VERSION 5.8 ;
BUSBITCHARS "[]" ;
DIVIDERCHAR "/" ;
UNITS
    DATABASE MICRONS 1000 ;
END UNITS

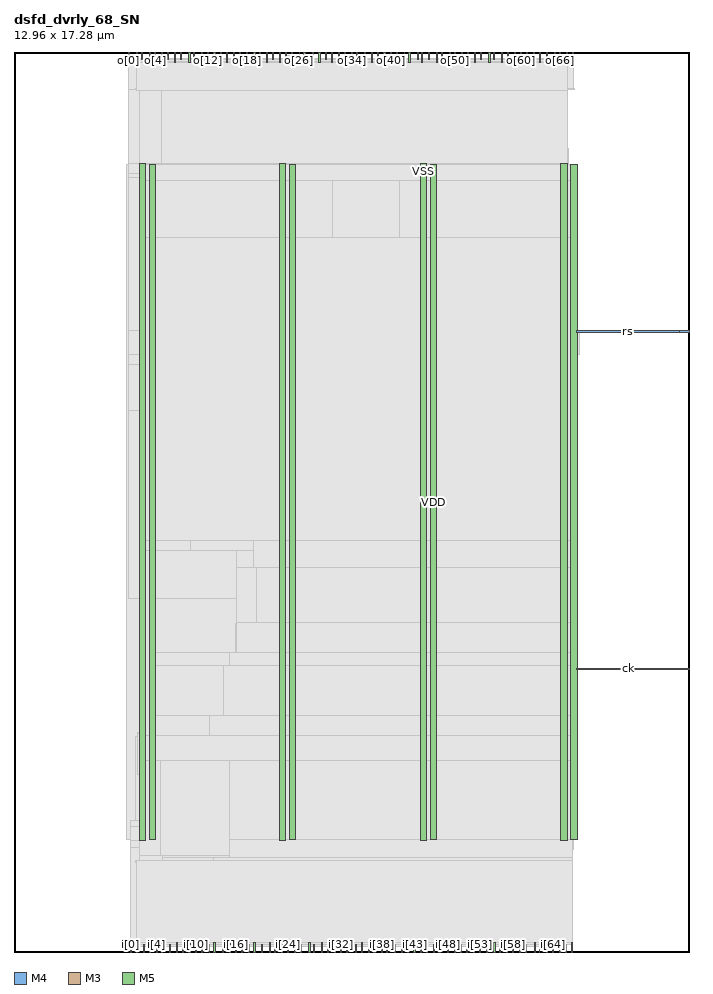
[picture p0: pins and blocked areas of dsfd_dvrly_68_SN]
MACRO dsfd_dvrly_68_SN
  FOREIGN dsfd_dvrly_68_SN 0 0 ;
  CLASS BLOCK ;
  SIZE 12.96 BY 17.28 ;
  PIN ck
    DIRECTION INPUT ;
    USE SIGNAL ;
    PORT
      LAYER M4 ;
        RECT  12.768 5.424 12.96 5.448 ;
    END
    PORT
      LAYER M4 ;
        RECT  10.804 5.424 12.78 5.448 ;
    END
  END ck
  PIN ck_o
    DIRECTION OUTPUT ;
    USE SIGNAL ;
    PORT
      LAYER M3 ;
        RECT  10.728 17.136 10.746 17.28 ;
    END
  END ck_o
  PIN i[0]
    DIRECTION INPUT ;
    USE SIGNAL ;
    PORT
      LAYER M3 ;
        RECT  2.232 0 2.25 0.144 ;
    END
  END i[0]
  PIN i[10]
    DIRECTION INPUT ;
    USE SIGNAL ;
    PORT
      LAYER M3 ;
        RECT  3.492 0 3.51 0.144 ;
    END
  END i[10]
  PIN i[11]
    DIRECTION INPUT ;
    USE SIGNAL ;
    PORT
      LAYER M5 ;
        RECT  3.6 0 3.624 0.192 ;
    END
  END i[11]
  PIN i[12]
    DIRECTION INPUT ;
    USE SIGNAL ;
    PORT
      LAYER M3 ;
        RECT  3.744 0 3.762 0.144 ;
    END
  END i[12]
  PIN i[13]
    DIRECTION INPUT ;
    USE SIGNAL ;
    PORT
      LAYER M5 ;
        RECT  3.84 0 3.864 0.192 ;
    END
  END i[13]
  PIN i[14]
    DIRECTION INPUT ;
    USE SIGNAL ;
    PORT
      LAYER M3 ;
        RECT  3.996 0 4.014 0.144 ;
    END
  END i[14]
  PIN i[15]
    DIRECTION INPUT ;
    USE SIGNAL ;
    PORT
      LAYER M5 ;
        RECT  4.128 0 4.152 0.192 ;
    END
  END i[15]
  PIN i[16]
    DIRECTION INPUT ;
    USE SIGNAL ;
    PORT
      LAYER M3 ;
        RECT  4.248 0 4.266 0.144 ;
    END
  END i[16]
  PIN i[17]
    DIRECTION INPUT ;
    USE SIGNAL ;
    PORT
      LAYER M5 ;
        RECT  4.368 0 4.392 0.192 ;
    END
  END i[17]
  PIN i[18]
    DIRECTION INPUT ;
    USE SIGNAL ;
    PORT
      LAYER M3 ;
        RECT  4.5 0 4.518 0.144 ;
    END
  END i[18]
  PIN i[19]
    DIRECTION INPUT ;
    USE SIGNAL ;
    PORT
      LAYER M5 ;
        RECT  4.608 0 4.632 0.192 ;
    END
  END i[19]
  PIN i[1]
    DIRECTION INPUT ;
    USE SIGNAL ;
    PORT
      LAYER M5 ;
        RECT  2.352 0 2.376 0.192 ;
    END
  END i[1]
  PIN i[20]
    DIRECTION INPUT ;
    USE SIGNAL ;
    PORT
      LAYER M3 ;
        RECT  4.752 0 4.77 0.144 ;
    END
  END i[20]
  PIN i[21]
    DIRECTION INPUT ;
    USE SIGNAL ;
    PORT
      LAYER M5 ;
        RECT  4.896 0 4.92 0.192 ;
    END
  END i[21]
  PIN i[22]
    DIRECTION INPUT ;
    USE SIGNAL ;
    PORT
      LAYER M3 ;
        RECT  5.004 0 5.022 0.144 ;
    END
  END i[22]
  PIN i[23]
    DIRECTION INPUT ;
    USE SIGNAL ;
    PORT
      LAYER M5 ;
        RECT  5.136 0 5.16 0.192 ;
    END
  END i[23]
  PIN i[24]
    DIRECTION INPUT ;
    USE SIGNAL ;
    PORT
      LAYER M3 ;
        RECT  5.256 0 5.274 0.144 ;
    END
  END i[24]
  PIN i[25]
    DIRECTION INPUT ;
    USE SIGNAL ;
    PORT
      LAYER M5 ;
        RECT  5.376 0 5.4 0.192 ;
    END
  END i[25]
  PIN i[26]
    DIRECTION INPUT ;
    USE SIGNAL ;
    PORT
      LAYER M3 ;
        RECT  5.508 0 5.526 0.144 ;
    END
  END i[26]
  PIN i[27]
    DIRECTION INPUT ;
    USE SIGNAL ;
    PORT
      LAYER M5 ;
        RECT  5.664 0 5.688 0.192 ;
    END
  END i[27]
  PIN i[28]
    DIRECTION INPUT ;
    USE SIGNAL ;
    PORT
      LAYER M3 ;
        RECT  5.76 0 5.778 0.144 ;
    END
  END i[28]
  PIN i[29]
    DIRECTION INPUT ;
    USE SIGNAL ;
    PORT
      LAYER M5 ;
        RECT  5.904 0 5.928 0.192 ;
    END
  END i[29]
  PIN i[2]
    DIRECTION INPUT ;
    USE SIGNAL ;
    PORT
      LAYER M3 ;
        RECT  2.484 0 2.502 0.144 ;
    END
  END i[2]
  PIN i[30]
    DIRECTION INPUT ;
    USE SIGNAL ;
    PORT
      LAYER M3 ;
        RECT  6.012 0 6.03 0.144 ;
    END
  END i[30]
  PIN i[31]
    DIRECTION INPUT ;
    USE SIGNAL ;
    PORT
      LAYER M5 ;
        RECT  6.144 0 6.168 0.192 ;
    END
  END i[31]
  PIN i[32]
    DIRECTION INPUT ;
    USE SIGNAL ;
    PORT
      LAYER M3 ;
        RECT  6.264 0 6.282 0.144 ;
    END
  END i[32]
  PIN i[33]
    DIRECTION INPUT ;
    USE SIGNAL ;
    PORT
      LAYER M5 ;
        RECT  6.384 0 6.408 0.192 ;
    END
  END i[33]
  PIN i[34]
    DIRECTION INPUT ;
    USE SIGNAL ;
    PORT
      LAYER M3 ;
        RECT  6.552 0 6.57 0.144 ;
    END
  END i[34]
  PIN i[35]
    DIRECTION INPUT ;
    USE SIGNAL ;
    PORT
      LAYER M5 ;
        RECT  6.672 0 6.696 0.192 ;
    END
  END i[35]
  PIN i[36]
    DIRECTION INPUT ;
    USE SIGNAL ;
    PORT
      LAYER M3 ;
        RECT  6.804 0 6.822 0.144 ;
    END
  END i[36]
  PIN i[37]
    DIRECTION INPUT ;
    USE SIGNAL ;
    PORT
      LAYER M5 ;
        RECT  6.912 0 6.936 0.192 ;
    END
  END i[37]
  PIN i[38]
    DIRECTION INPUT ;
    USE SIGNAL ;
    PORT
      LAYER M3 ;
        RECT  7.056 0 7.074 0.144 ;
    END
  END i[38]
  PIN i[39]
    DIRECTION INPUT ;
    USE SIGNAL ;
    PORT
      LAYER M5 ;
        RECT  7.152 0 7.176 0.192 ;
    END
  END i[39]
  PIN i[3]
    DIRECTION INPUT ;
    USE SIGNAL ;
    PORT
      LAYER M5 ;
        RECT  2.592 0 2.616 0.192 ;
    END
  END i[3]
  PIN i[40]
    DIRECTION INPUT ;
    USE SIGNAL ;
    PORT
      LAYER M3 ;
        RECT  7.308 0 7.326 0.144 ;
    END
  END i[40]
  PIN i[41]
    DIRECTION INPUT ;
    USE SIGNAL ;
    PORT
      LAYER M5 ;
        RECT  7.44 0 7.464 0.192 ;
    END
  END i[41]
  PIN i[42]
    DIRECTION INPUT ;
    USE SIGNAL ;
    PORT
      LAYER M3 ;
        RECT  7.56 0 7.578 0.144 ;
    END
  END i[42]
  PIN i[43]
    DIRECTION INPUT ;
    USE SIGNAL ;
    PORT
      LAYER M5 ;
        RECT  7.68 0 7.704 0.192 ;
    END
  END i[43]
  PIN i[44]
    DIRECTION INPUT ;
    USE SIGNAL ;
    PORT
      LAYER M3 ;
        RECT  7.812 0 7.83 0.144 ;
    END
  END i[44]
  PIN i[45]
    DIRECTION INPUT ;
    USE SIGNAL ;
    PORT
      LAYER M5 ;
        RECT  7.92 0 7.944 0.192 ;
    END
  END i[45]
  PIN i[46]
    DIRECTION INPUT ;
    USE SIGNAL ;
    PORT
      LAYER M3 ;
        RECT  8.064 0 8.082 0.144 ;
    END
  END i[46]
  PIN i[47]
    DIRECTION INPUT ;
    USE SIGNAL ;
    PORT
      LAYER M5 ;
        RECT  8.16 0 8.184 0.192 ;
    END
  END i[47]
  PIN i[48]
    DIRECTION INPUT ;
    USE SIGNAL ;
    PORT
      LAYER M3 ;
        RECT  8.316 0 8.334 0.144 ;
    END
  END i[48]
  PIN i[49]
    DIRECTION INPUT ;
    USE SIGNAL ;
    PORT
      LAYER M5 ;
        RECT  8.448 0 8.472 0.192 ;
    END
  END i[49]
  PIN i[4]
    DIRECTION INPUT ;
    USE SIGNAL ;
    PORT
      LAYER M3 ;
        RECT  2.736 0 2.754 0.144 ;
    END
  END i[4]
  PIN i[50]
    DIRECTION INPUT ;
    USE SIGNAL ;
    PORT
      LAYER M3 ;
        RECT  8.568 0 8.586 0.144 ;
    END
  END i[50]
  PIN i[51]
    DIRECTION INPUT ;
    USE SIGNAL ;
    PORT
      LAYER M5 ;
        RECT  8.688 0 8.712 0.192 ;
    END
  END i[51]
  PIN i[52]
    DIRECTION INPUT ;
    USE SIGNAL ;
    PORT
      LAYER M3 ;
        RECT  8.82 0 8.838 0.144 ;
    END
  END i[52]
  PIN i[53]
    DIRECTION INPUT ;
    USE SIGNAL ;
    PORT
      LAYER M5 ;
        RECT  8.928 0 8.952 0.192 ;
    END
  END i[53]
  PIN i[54]
    DIRECTION INPUT ;
    USE SIGNAL ;
    PORT
      LAYER M3 ;
        RECT  9.072 0 9.09 0.144 ;
    END
  END i[54]
  PIN i[55]
    DIRECTION INPUT ;
    USE SIGNAL ;
    PORT
      LAYER M5 ;
        RECT  9.216 0 9.24 0.192 ;
    END
  END i[55]
  PIN i[56]
    DIRECTION INPUT ;
    USE SIGNAL ;
    PORT
      LAYER M3 ;
        RECT  9.324 0 9.342 0.144 ;
    END
  END i[56]
  PIN i[57]
    DIRECTION INPUT ;
    USE SIGNAL ;
    PORT
      LAYER M5 ;
        RECT  9.456 0 9.48 0.192 ;
    END
  END i[57]
  PIN i[58]
    DIRECTION INPUT ;
    USE SIGNAL ;
    PORT
      LAYER M3 ;
        RECT  9.576 0 9.594 0.144 ;
    END
  END i[58]
  PIN i[59]
    DIRECTION INPUT ;
    USE SIGNAL ;
    PORT
      LAYER M5 ;
        RECT  9.696 0 9.72 0.192 ;
    END
  END i[59]
  PIN i[5]
    DIRECTION INPUT ;
    USE SIGNAL ;
    PORT
      LAYER M5 ;
        RECT  2.832 0 2.856 0.192 ;
    END
  END i[5]
  PIN i[60]
    DIRECTION INPUT ;
    USE SIGNAL ;
    PORT
      LAYER M3 ;
        RECT  9.828 0 9.846 0.144 ;
    END
  END i[60]
  PIN i[61]
    DIRECTION INPUT ;
    USE SIGNAL ;
    PORT
      LAYER M5 ;
        RECT  9.984 0 10.008 0.192 ;
    END
  END i[61]
  PIN i[62]
    DIRECTION INPUT ;
    USE SIGNAL ;
    PORT
      LAYER M3 ;
        RECT  10.08 0 10.098 0.144 ;
    END
  END i[62]
  PIN i[63]
    DIRECTION INPUT ;
    USE SIGNAL ;
    PORT
      LAYER M5 ;
        RECT  10.224 0 10.248 0.192 ;
    END
  END i[63]
  PIN i[64]
    DIRECTION INPUT ;
    USE SIGNAL ;
    PORT
      LAYER M3 ;
        RECT  10.332 0 10.35 0.144 ;
    END
  END i[64]
  PIN i[65]
    DIRECTION INPUT ;
    USE SIGNAL ;
    PORT
      LAYER M5 ;
        RECT  10.464 0 10.488 0.192 ;
    END
  END i[65]
  PIN i[66]
    DIRECTION INPUT ;
    USE SIGNAL ;
    PORT
      LAYER M3 ;
        RECT  10.584 0 10.602 0.144 ;
    END
  END i[66]
  PIN i[67]
    DIRECTION INPUT ;
    USE SIGNAL ;
    PORT
      LAYER M5 ;
        RECT  10.704 0 10.728 0.192 ;
    END
  END i[67]
  PIN i[6]
    DIRECTION INPUT ;
    USE SIGNAL ;
    PORT
      LAYER M3 ;
        RECT  2.988 0 3.006 0.144 ;
    END
  END i[6]
  PIN i[7]
    DIRECTION INPUT ;
    USE SIGNAL ;
    PORT
      LAYER M5 ;
        RECT  3.12 0 3.144 0.192 ;
    END
  END i[7]
  PIN i[8]
    DIRECTION INPUT ;
    USE SIGNAL ;
    PORT
      LAYER M3 ;
        RECT  3.24 0 3.258 0.144 ;
    END
  END i[8]
  PIN i[9]
    DIRECTION INPUT ;
    USE SIGNAL ;
    PORT
      LAYER M5 ;
        RECT  3.36 0 3.384 0.192 ;
    END
  END i[9]
  PIN o[0]
    DIRECTION OUTPUT ;
    USE SIGNAL ;
    PORT
      LAYER M3 ;
        RECT  2.196 17.136 2.214 17.28 ;
    END
  END o[0]
  PIN o[10]
    DIRECTION OUTPUT ;
    USE SIGNAL ;
    PORT
      LAYER M3 ;
        RECT  3.456 17.136 3.474 17.28 ;
    END
  END o[10]
  PIN o[11]
    DIRECTION OUTPUT ;
    USE SIGNAL ;
    PORT
      LAYER M5 ;
        RECT  3.6 17.088 3.624 17.28 ;
    END
  END o[11]
  PIN o[12]
    DIRECTION OUTPUT ;
    USE SIGNAL ;
    PORT
      LAYER M3 ;
        RECT  3.708 17.136 3.726 17.28 ;
    END
  END o[12]
  PIN o[13]
    DIRECTION OUTPUT ;
    USE SIGNAL ;
    PORT
      LAYER M5 ;
        RECT  3.84 17.088 3.864 17.28 ;
    END
  END o[13]
  PIN o[14]
    DIRECTION OUTPUT ;
    USE SIGNAL ;
    PORT
      LAYER M3 ;
        RECT  3.96 17.136 3.978 17.28 ;
    END
  END o[14]
  PIN o[15]
    DIRECTION OUTPUT ;
    USE SIGNAL ;
    PORT
      LAYER M5 ;
        RECT  4.08 17.088 4.104 17.28 ;
    END
  END o[15]
  PIN o[16]
    DIRECTION OUTPUT ;
    USE SIGNAL ;
    PORT
      LAYER M3 ;
        RECT  4.212 17.136 4.23 17.28 ;
    END
  END o[16]
  PIN o[17]
    DIRECTION OUTPUT ;
    USE SIGNAL ;
    PORT
      LAYER M5 ;
        RECT  4.32 17.088 4.344 17.28 ;
    END
  END o[17]
  PIN o[18]
    DIRECTION OUTPUT ;
    USE SIGNAL ;
    PORT
      LAYER M3 ;
        RECT  4.464 17.136 4.482 17.28 ;
    END
  END o[18]
  PIN o[19]
    DIRECTION OUTPUT ;
    USE SIGNAL ;
    PORT
      LAYER M5 ;
        RECT  4.608 17.088 4.632 17.28 ;
    END
  END o[19]
  PIN o[1]
    DIRECTION OUTPUT ;
    USE SIGNAL ;
    PORT
      LAYER M5 ;
        RECT  2.352 17.088 2.376 17.28 ;
    END
  END o[1]
  PIN o[20]
    DIRECTION OUTPUT ;
    USE SIGNAL ;
    PORT
      LAYER M3 ;
        RECT  4.716 17.136 4.734 17.28 ;
    END
  END o[20]
  PIN o[21]
    DIRECTION OUTPUT ;
    USE SIGNAL ;
    PORT
      LAYER M5 ;
        RECT  4.848 17.088 4.872 17.28 ;
    END
  END o[21]
  PIN o[22]
    DIRECTION OUTPUT ;
    USE SIGNAL ;
    PORT
      LAYER M3 ;
        RECT  4.968 17.136 4.986 17.28 ;
    END
  END o[22]
  PIN o[23]
    DIRECTION OUTPUT ;
    USE SIGNAL ;
    PORT
      LAYER M5 ;
        RECT  5.088 17.088 5.112 17.28 ;
    END
  END o[23]
  PIN o[24]
    DIRECTION OUTPUT ;
    USE SIGNAL ;
    PORT
      LAYER M3 ;
        RECT  5.22 17.136 5.238 17.28 ;
    END
  END o[24]
  PIN o[25]
    DIRECTION OUTPUT ;
    USE SIGNAL ;
    PORT
      LAYER M5 ;
        RECT  5.328 17.088 5.352 17.28 ;
    END
  END o[25]
  PIN o[26]
    DIRECTION OUTPUT ;
    USE SIGNAL ;
    PORT
      LAYER M3 ;
        RECT  5.472 17.136 5.49 17.28 ;
    END
  END o[26]
  PIN o[27]
    DIRECTION OUTPUT ;
    USE SIGNAL ;
    PORT
      LAYER M5 ;
        RECT  5.568 17.088 5.592 17.28 ;
    END
  END o[27]
  PIN o[28]
    DIRECTION OUTPUT ;
    USE SIGNAL ;
    PORT
      LAYER M3 ;
        RECT  5.724 17.136 5.742 17.28 ;
    END
  END o[28]
  PIN o[29]
    DIRECTION OUTPUT ;
    USE SIGNAL ;
    PORT
      LAYER M5 ;
        RECT  5.856 17.088 5.88 17.28 ;
    END
  END o[29]
  PIN o[2]
    DIRECTION OUTPUT ;
    USE SIGNAL ;
    PORT
      LAYER M3 ;
        RECT  2.448 17.136 2.466 17.28 ;
    END
  END o[2]
  PIN o[30]
    DIRECTION OUTPUT ;
    USE SIGNAL ;
    PORT
      LAYER M3 ;
        RECT  5.976 17.136 5.994 17.28 ;
    END
  END o[30]
  PIN o[31]
    DIRECTION OUTPUT ;
    USE SIGNAL ;
    PORT
      LAYER M5 ;
        RECT  6.096 17.088 6.12 17.28 ;
    END
  END o[31]
  PIN o[32]
    DIRECTION OUTPUT ;
    USE SIGNAL ;
    PORT
      LAYER M3 ;
        RECT  6.228 17.136 6.246 17.28 ;
    END
  END o[32]
  PIN o[33]
    DIRECTION OUTPUT ;
    USE SIGNAL ;
    PORT
      LAYER M5 ;
        RECT  6.336 17.088 6.36 17.28 ;
    END
  END o[33]
  PIN o[34]
    DIRECTION OUTPUT ;
    USE SIGNAL ;
    PORT
      LAYER M3 ;
        RECT  6.48 17.136 6.498 17.28 ;
    END
  END o[34]
  PIN o[35]
    DIRECTION OUTPUT ;
    USE SIGNAL ;
    PORT
      LAYER M5 ;
        RECT  6.576 17.088 6.6 17.28 ;
    END
  END o[35]
  PIN o[36]
    DIRECTION OUTPUT ;
    USE SIGNAL ;
    PORT
      LAYER M3 ;
        RECT  6.732 17.136 6.75 17.28 ;
    END
  END o[36]
  PIN o[37]
    DIRECTION OUTPUT ;
    USE SIGNAL ;
    PORT
      LAYER M5 ;
        RECT  6.864 17.088 6.888 17.28 ;
    END
  END o[37]
  PIN o[38]
    DIRECTION OUTPUT ;
    USE SIGNAL ;
    PORT
      LAYER M3 ;
        RECT  6.984 17.136 7.002 17.28 ;
    END
  END o[38]
  PIN o[39]
    DIRECTION OUTPUT ;
    USE SIGNAL ;
    PORT
      LAYER M5 ;
        RECT  7.104 17.088 7.128 17.28 ;
    END
  END o[39]
  PIN o[3]
    DIRECTION OUTPUT ;
    USE SIGNAL ;
    PORT
      LAYER M5 ;
        RECT  2.592 17.088 2.616 17.28 ;
    END
  END o[3]
  PIN o[40]
    DIRECTION OUTPUT ;
    USE SIGNAL ;
    PORT
      LAYER M3 ;
        RECT  7.236 17.136 7.254 17.28 ;
    END
  END o[40]
  PIN o[41]
    DIRECTION OUTPUT ;
    USE SIGNAL ;
    PORT
      LAYER M5 ;
        RECT  7.344 17.088 7.368 17.28 ;
    END
  END o[41]
  PIN o[42]
    DIRECTION OUTPUT ;
    USE SIGNAL ;
    PORT
      LAYER M3 ;
        RECT  7.488 17.136 7.506 17.28 ;
    END
  END o[42]
  PIN o[43]
    DIRECTION OUTPUT ;
    USE SIGNAL ;
    PORT
      LAYER M5 ;
        RECT  7.584 17.088 7.608 17.28 ;
    END
  END o[43]
  PIN o[44]
    DIRECTION OUTPUT ;
    USE SIGNAL ;
    PORT
      LAYER M3 ;
        RECT  7.74 17.136 7.758 17.28 ;
    END
  END o[44]
  PIN o[45]
    DIRECTION OUTPUT ;
    USE SIGNAL ;
    PORT
      LAYER M5 ;
        RECT  7.824 17.088 7.848 17.28 ;
    END
  END o[45]
  PIN o[46]
    DIRECTION OUTPUT ;
    USE SIGNAL ;
    PORT
      LAYER M3 ;
        RECT  7.956 17.136 7.974 17.28 ;
    END
  END o[46]
  PIN o[47]
    DIRECTION OUTPUT ;
    USE SIGNAL ;
    PORT
      LAYER M5 ;
        RECT  8.112 17.088 8.136 17.28 ;
    END
  END o[47]
  PIN o[48]
    DIRECTION OUTPUT ;
    USE SIGNAL ;
    PORT
      LAYER M3 ;
        RECT  8.208 17.136 8.226 17.28 ;
    END
  END o[48]
  PIN o[49]
    DIRECTION OUTPUT ;
    USE SIGNAL ;
    PORT
      LAYER M5 ;
        RECT  8.352 17.088 8.376 17.28 ;
    END
  END o[49]
  PIN o[4]
    DIRECTION OUTPUT ;
    USE SIGNAL ;
    PORT
      LAYER M3 ;
        RECT  2.7 17.136 2.718 17.28 ;
    END
  END o[4]
  PIN o[50]
    DIRECTION OUTPUT ;
    USE SIGNAL ;
    PORT
      LAYER M3 ;
        RECT  8.46 17.136 8.478 17.28 ;
    END
  END o[50]
  PIN o[51]
    DIRECTION OUTPUT ;
    USE SIGNAL ;
    PORT
      LAYER M5 ;
        RECT  8.592 17.088 8.616 17.28 ;
    END
  END o[51]
  PIN o[52]
    DIRECTION OUTPUT ;
    USE SIGNAL ;
    PORT
      LAYER M3 ;
        RECT  8.712 17.136 8.73 17.28 ;
    END
  END o[52]
  PIN o[53]
    DIRECTION OUTPUT ;
    USE SIGNAL ;
    PORT
      LAYER M5 ;
        RECT  8.832 17.088 8.856 17.28 ;
    END
  END o[53]
  PIN o[54]
    DIRECTION OUTPUT ;
    USE SIGNAL ;
    PORT
      LAYER M3 ;
        RECT  8.964 17.136 8.982 17.28 ;
    END
  END o[54]
  PIN o[55]
    DIRECTION OUTPUT ;
    USE SIGNAL ;
    PORT
      LAYER M5 ;
        RECT  9.12 17.088 9.144 17.28 ;
    END
  END o[55]
  PIN o[56]
    DIRECTION OUTPUT ;
    USE SIGNAL ;
    PORT
      LAYER M3 ;
        RECT  9.216 17.136 9.234 17.28 ;
    END
  END o[56]
  PIN o[57]
    DIRECTION OUTPUT ;
    USE SIGNAL ;
    PORT
      LAYER M5 ;
        RECT  9.36 17.088 9.384 17.28 ;
    END
  END o[57]
  PIN o[58]
    DIRECTION OUTPUT ;
    USE SIGNAL ;
    PORT
      LAYER M3 ;
        RECT  9.468 17.136 9.486 17.28 ;
    END
  END o[58]
  PIN o[59]
    DIRECTION OUTPUT ;
    USE SIGNAL ;
    PORT
      LAYER M5 ;
        RECT  9.6 17.088 9.624 17.28 ;
    END
  END o[59]
  PIN o[5]
    DIRECTION OUTPUT ;
    USE SIGNAL ;
    PORT
      LAYER M5 ;
        RECT  2.832 17.088 2.856 17.28 ;
    END
  END o[5]
  PIN o[60]
    DIRECTION OUTPUT ;
    USE SIGNAL ;
    PORT
      LAYER M3 ;
        RECT  9.72 17.136 9.738 17.28 ;
    END
  END o[60]
  PIN o[61]
    DIRECTION OUTPUT ;
    USE SIGNAL ;
    PORT
      LAYER M5 ;
        RECT  9.84 17.088 9.864 17.28 ;
    END
  END o[61]
  PIN o[62]
    DIRECTION OUTPUT ;
    USE SIGNAL ;
    PORT
      LAYER M3 ;
        RECT  9.972 17.136 9.99 17.28 ;
    END
  END o[62]
  PIN o[63]
    DIRECTION OUTPUT ;
    USE SIGNAL ;
    PORT
      LAYER M5 ;
        RECT  10.08 17.088 10.104 17.28 ;
    END
  END o[63]
  PIN o[64]
    DIRECTION OUTPUT ;
    USE SIGNAL ;
    PORT
      LAYER M3 ;
        RECT  10.224 17.136 10.242 17.28 ;
    END
  END o[64]
  PIN o[65]
    DIRECTION OUTPUT ;
    USE SIGNAL ;
    PORT
      LAYER M5 ;
        RECT  10.368 17.088 10.392 17.28 ;
    END
  END o[65]
  PIN o[66]
    DIRECTION OUTPUT ;
    USE SIGNAL ;
    PORT
      LAYER M3 ;
        RECT  10.476 17.136 10.494 17.28 ;
    END
  END o[66]
  PIN o[67]
    DIRECTION OUTPUT ;
    USE SIGNAL ;
    PORT
      LAYER M5 ;
        RECT  10.608 17.088 10.632 17.28 ;
    END
  END o[67]
  PIN o[6]
    DIRECTION OUTPUT ;
    USE SIGNAL ;
    PORT
      LAYER M3 ;
        RECT  2.952 17.136 2.97 17.28 ;
    END
  END o[6]
  PIN o[7]
    DIRECTION OUTPUT ;
    USE SIGNAL ;
    PORT
      LAYER M5 ;
        RECT  3.072 17.088 3.096 17.28 ;
    END
  END o[7]
  PIN o[8]
    DIRECTION OUTPUT ;
    USE SIGNAL ;
    PORT
      LAYER M3 ;
        RECT  3.204 17.136 3.222 17.28 ;
    END
  END o[8]
  PIN o[9]
    DIRECTION OUTPUT ;
    USE SIGNAL ;
    PORT
      LAYER M5 ;
        RECT  3.36 17.088 3.384 17.28 ;
    END
  END o[9]
  PIN rs
    DIRECTION INPUT ;
    USE SIGNAL ;
    PORT
      LAYER M4 ;
        RECT  12.768 11.904 12.96 11.928 ;
    END
    PORT
      LAYER M4 ;
        RECT  10.804 11.904 12.78 11.928 ;
    END
  END rs
  PIN VDD
    DIRECTION INOUT ;
    USE POWER ;
    PORT
      LAYER M5 ;
        RECT  10.692 2.151 10.812 15.129 ;
        RECT  7.992 2.151 8.112 15.129 ;
        RECT  5.292 2.151 5.412 15.129 ;
        RECT  2.592 2.151 2.712 15.129 ;
    END
  END VDD
  PIN VSS
    DIRECTION INOUT ;
    USE GROUND ;
    PORT
      LAYER M5 ;
        RECT  10.5 2.137 10.62 15.143 ;
        RECT  7.8 2.137 7.92 15.143 ;
        RECT  5.1 2.137 5.22 15.143 ;
        RECT  2.4 2.137 2.52 15.143 ;
    END
  END VSS
  # OT_OBS_CLOSED layer=M5 d_um=1.536 added=11
  OBS
    LAYER RVTN ;
     RECT  2.16 2.16 10.8 2.295 ;
     RECT  2.16 2.565 10.8 2.835 ;
     RECT  2.16 3.105 10.8 3.375 ;
     RECT  2.16 3.645 10.8 3.915 ;
     RECT  2.16 4.185 10.8 4.455 ;
     RECT  2.16 4.725 10.8 4.995 ;
     RECT  2.16 5.265 10.8 5.535 ;
     RECT  2.16 5.805 10.8 6.075 ;
     RECT  2.16 6.345 10.8 6.615 ;
     RECT  2.16 6.885 10.8 7.155 ;
     RECT  2.16 7.425 10.8 7.695 ;
     RECT  2.16 7.965 10.8 8.235 ;
     RECT  2.16 8.505 10.8 8.775 ;
     RECT  2.16 9.045 10.8 9.315 ;
     RECT  2.16 9.585 10.8 9.855 ;
     RECT  2.16 10.125 10.8 10.395 ;
     RECT  2.16 10.665 10.8 10.935 ;
     RECT  2.16 11.205 10.8 11.475 ;
     RECT  2.16 11.745 10.8 12.015 ;
     RECT  2.16 12.285 10.8 12.555 ;
     RECT  2.16 12.825 10.8 13.095 ;
     RECT  2.16 13.365 10.8 13.635 ;
     RECT  2.16 13.905 10.8 14.175 ;
     RECT  2.16 14.445 10.8 14.715 ;
     RECT  2.16 14.985 10.8 15.12 ;
    LAYER RVTP ;
     RECT  2.16 2.295 10.8 2.565 ;
     RECT  2.16 2.835 10.8 3.105 ;
     RECT  2.16 3.375 10.8 3.645 ;
     RECT  2.16 3.915 10.8 4.185 ;
     RECT  2.16 4.455 10.8 4.725 ;
     RECT  2.16 4.995 10.8 5.265 ;
     RECT  2.16 5.535 10.8 5.805 ;
     RECT  2.16 6.075 10.8 6.345 ;
     RECT  2.16 6.615 10.8 6.885 ;
     RECT  2.16 7.155 10.8 7.425 ;
     RECT  2.16 7.695 10.8 7.965 ;
     RECT  2.16 8.235 10.8 8.505 ;
     RECT  2.16 8.775 10.8 9.045 ;
     RECT  2.16 9.315 10.8 9.585 ;
     RECT  2.16 9.855 10.8 10.125 ;
     RECT  2.16 10.395 10.8 10.665 ;
     RECT  2.16 10.935 10.8 11.205 ;
     RECT  2.16 11.475 10.8 11.745 ;
     RECT  2.16 12.015 10.8 12.285 ;
     RECT  2.16 12.555 10.8 12.825 ;
     RECT  2.16 13.095 10.8 13.365 ;
     RECT  2.16 13.635 10.8 13.905 ;
     RECT  2.16 14.175 10.8 14.445 ;
     RECT  2.16 14.715 10.8 14.985 ;
    LAYER M1 ;
     RECT  2.16 2.151 10.8 15.129 ;
    LAYER M2 ;
     RECT  2.16 2.151 2.623 15.129 ;
     RECT  2.443 16.542 2.695 16.56 ;
     RECT  2.623 1.728 2.759 15.129 ;
     RECT  2.695 16.542 2.947 16.632 ;
     RECT  2.947 16.542 3.083 16.704 ;
     RECT  3.083 16.614 3.191 16.704 ;
     RECT  3.559 1.152 3.659 1.17 ;
     RECT  2.759 2.151 3.847 15.129 ;
     RECT  3.847 2.106 3.947 15.129 ;
     RECT  3.191 16.686 3.947 16.704 ;
     RECT  3.947 2.151 4.855 15.129 ;
     RECT  5.215 17.118 5.251 17.136 ;
     RECT  5.251 17.118 5.351 17.208 ;
     RECT  4.855 2.106 5.639 15.129 ;
     RECT  5.639 2.151 6.979 15.129 ;
     RECT  6.547 1.152 7.007 1.17 ;
     RECT  7.231 17.118 7.267 17.136 ;
     RECT  7.267 17.118 7.367 17.208 ;
     RECT  6.979 2.151 7.915 15.174 ;
     RECT  2.479 0.144 8.195 0.162 ;
     RECT  7.915 2.07 8.591 15.174 ;
     RECT  8.591 2.07 8.815 15.129 ;
     RECT  8.563 0.306 8.959 0.324 ;
     RECT  8.959 0.144 9.095 0.324 ;
     RECT  8.815 1.728 9.347 15.129 ;
     RECT  9.715 17.118 9.751 17.136 ;
     RECT  9.751 17.118 9.851 17.208 ;
     RECT  9.347 2.151 9.967 15.129 ;
     RECT  9.967 2.151 10.103 15.516 ;
     RECT  9.095 0.144 10.607 0.162 ;
     RECT  10.103 2.151 10.8 15.129 ;
     RECT  10.8 2.421 10.812 14.859 ;
     RECT  10.812 11.484 10.859 11.502 ;
    LAYER M3 ;
     RECT  2.25 0.108 2.484 0.144 ;
     RECT  2.502 0.108 2.736 0.144 ;
     RECT  2.754 0.108 2.988 0.144 ;
     RECT  3.006 0.108 3.24 0.144 ;
     RECT  3.258 0.108 3.492 0.144 ;
     RECT  3.51 0.108 3.744 0.144 ;
     RECT  3.762 0.108 3.996 0.144 ;
     RECT  4.014 0.108 4.248 0.144 ;
     RECT  4.266 0.108 4.5 0.144 ;
     RECT  4.518 0.108 4.752 0.144 ;
     RECT  4.77 0.108 5.004 0.144 ;
     RECT  5.022 0.108 5.256 0.144 ;
     RECT  5.274 0.108 5.508 0.144 ;
     RECT  5.526 0.108 5.76 0.144 ;
     RECT  5.778 0.108 6.012 0.144 ;
     RECT  6.03 0.108 6.264 0.144 ;
     RECT  6.282 0.108 6.552 0.144 ;
     RECT  6.57 0.108 6.804 0.144 ;
     RECT  6.822 0.108 7.056 0.144 ;
     RECT  7.074 0.108 7.308 0.144 ;
     RECT  7.326 0.108 7.56 0.144 ;
     RECT  7.578 0.108 7.812 0.144 ;
     RECT  7.83 0.108 8.064 0.144 ;
     RECT  8.082 0.108 8.316 0.144 ;
     RECT  8.334 0.108 8.568 0.144 ;
     RECT  8.586 0.108 8.82 0.144 ;
     RECT  8.838 0.108 9.072 0.144 ;
     RECT  9.09 0.108 9.324 0.144 ;
     RECT  9.342 0.108 9.576 0.144 ;
     RECT  9.594 0.108 9.828 0.144 ;
     RECT  9.846 0.108 10.08 0.144 ;
     RECT  10.098 0.108 10.332 0.144 ;
     RECT  10.35 0.108 10.584 0.144 ;
     RECT  2.232 0.144 10.602 0.167 ;
     RECT  2.232 0.167 10.422 2.011 ;
     RECT  2.232 2.011 10.458 2.143 ;
     RECT  2.232 2.143 10.605 2.413 ;
     RECT  2.232 2.413 10.797 2.525 ;
     RECT  2.34 2.525 10.797 4.145 ;
     RECT  2.376 4.145 10.797 4.205 ;
     RECT  2.415 4.205 10.797 6.781 ;
     RECT  2.196 6.781 10.797 10.391 ;
     RECT  2.196 10.391 8.097 11.281 ;
     RECT  8.856 10.391 10.797 11.281 ;
     RECT  2.196 11.281 10.797 11.479 ;
     RECT  2.196 11.479 10.854 11.933 ;
     RECT  2.196 11.933 10.797 14.867 ;
     RECT  2.196 14.867 10.674 14.945 ;
     RECT  2.196 14.945 10.605 15.137 ;
     RECT  2.196 15.137 10.494 16.555 ;
     RECT  2.196 16.555 10.746 17.136 ;
     RECT  2.214 17.136 2.448 17.148 ;
     RECT  2.466 17.136 2.7 17.148 ;
     RECT  2.718 17.136 2.952 17.148 ;
     RECT  2.97 17.136 3.204 17.148 ;
     RECT  3.222 17.136 3.456 17.148 ;
     RECT  3.474 17.136 3.708 17.148 ;
     RECT  3.726 17.136 3.96 17.148 ;
     RECT  3.978 17.136 4.212 17.148 ;
     RECT  4.23 17.136 4.464 17.148 ;
     RECT  4.482 17.136 4.716 17.148 ;
     RECT  4.734 17.136 4.968 17.148 ;
     RECT  4.986 17.136 5.22 17.148 ;
     RECT  5.238 17.136 5.472 17.148 ;
     RECT  5.49 17.136 5.724 17.148 ;
     RECT  5.742 17.136 5.976 17.148 ;
     RECT  5.994 17.136 6.228 17.148 ;
     RECT  6.246 17.136 6.48 17.148 ;
     RECT  6.498 17.136 6.732 17.148 ;
     RECT  6.75 17.136 6.984 17.148 ;
     RECT  7.002 17.136 7.236 17.148 ;
     RECT  7.254 17.136 7.488 17.148 ;
     RECT  7.506 17.136 7.74 17.148 ;
     RECT  7.758 17.136 7.956 17.148 ;
     RECT  7.974 17.136 8.208 17.148 ;
     RECT  8.226 17.136 8.46 17.148 ;
     RECT  8.478 17.136 8.712 17.148 ;
     RECT  8.73 17.136 8.964 17.148 ;
     RECT  8.982 17.136 9.216 17.148 ;
     RECT  9.234 17.136 9.468 17.148 ;
     RECT  9.486 17.136 9.72 17.148 ;
     RECT  9.738 17.136 9.972 17.148 ;
     RECT  9.99 17.136 10.224 17.148 ;
     RECT  10.242 17.136 10.476 17.148 ;
     RECT  10.494 17.136 10.728 17.148 ;
     RECT  5.256 17.148 5.346 17.213 ;
     RECT  7.272 17.148 7.362 17.213 ;
     RECT  9.756 17.148 9.846 17.213 ;
    LAYER M4 ;
     RECT  2.329 1.728 2.408 1.752 ;
     RECT  2.365 3.408 2.408 4.2 ;
     RECT  2.408 1.728 2.512 15.132 ;
     RECT  2.341 16.56 2.581 16.584 ;
     RECT  2.512 1.728 2.704 14.862 ;
     RECT  2.581 0.288 2.819 0.312 ;
     RECT  2.704 1.728 2.867 1.848 ;
     RECT  2.581 16.56 3.017 16.632 ;
     RECT  2.704 10.8 3.125 10.824 ;
     RECT  2.704 9.072 3.449 9.432 ;
     RECT  2.867 1.728 3.737 1.8 ;
     RECT  3.737 1.776 3.875 1.8 ;
     RECT  3.877 2.304 3.913 2.328 ;
     RECT  2.704 3.408 3.913 4.776 ;
     RECT  3.829 14.832 3.989 14.856 ;
     RECT  3.913 2.304 4.021 4.776 ;
     RECT  4.021 2.304 4.117 5.496 ;
     RECT  4.117 2.304 4.261 5.736 ;
     RECT  2.704 7.728 4.309 7.752 ;
     RECT  4.309 7.728 4.597 7.944 ;
     RECT  4.597 7.392 4.837 7.944 ;
     RECT  3.449 9.072 4.837 9.096 ;
     RECT  4.261 2.304 5.108 6.312 ;
     RECT  4.837 7.392 5.108 9.096 ;
     RECT  4.561 12 5.108 12.024 ;
     RECT  5.108 2.148 5.317 15.132 ;
     RECT  5.317 2.148 5.365 15.24 ;
     RECT  5.365 1.824 5.404 15.24 ;
     RECT  5.404 1.824 5.509 3.384 ;
     RECT  5.125 0.192 5.555 0.216 ;
     RECT  5.509 1.248 5.557 3.384 ;
     RECT  5.557 1.152 5.644 3.384 ;
     RECT  5.404 4.56 5.681 9.096 ;
     RECT  5.644 1.152 5.699 2.904 ;
     RECT  5.681 7.92 5.717 9.096 ;
     RECT  5.717 7.92 5.825 7.944 ;
     RECT  5.404 12 5.833 12.024 ;
     RECT  3.017 16.56 6.041 16.584 ;
     RECT  5.404 14.832 6.325 15.24 ;
     RECT  5.699 1.728 6.661 2.904 ;
     RECT  6.661 1.152 6.707 2.904 ;
     RECT  5.681 4.56 6.757 6.888 ;
     RECT  6.707 1.152 6.803 1.752 ;
     RECT  6.803 1.728 6.947 1.752 ;
     RECT  6.707 2.832 6.997 2.904 ;
     RECT  6.757 3.936 6.997 6.888 ;
     RECT  6.325 14.832 7.157 15.432 ;
     RECT  6.541 13.68 7.381 13.704 ;
     RECT  7.157 14.832 7.381 15.288 ;
     RECT  6.997 2.832 7.573 6.888 ;
     RECT  7.573 2.832 7.808 6.936 ;
     RECT  5.717 9.072 7.808 9.096 ;
     RECT  6.433 12.528 7.808 12.552 ;
     RECT  7.381 13.68 7.808 15.288 ;
     RECT  7.808 2.148 7.909 15.288 ;
     RECT  7.909 1.728 8.104 15.288 ;
     RECT  8.104 1.728 8.129 8.232 ;
     RECT  8.104 14.784 8.417 15.288 ;
     RECT  8.417 14.784 8.525 14.856 ;
     RECT  8.701 16.56 8.785 16.584 ;
     RECT  8.104 13.68 9.109 13.704 ;
     RECT  8.129 1.728 9.277 2.28 ;
     RECT  8.129 3.312 9.277 8.232 ;
     RECT  9.109 13.488 9.313 13.704 ;
     RECT  8.525 14.784 9.313 14.808 ;
     RECT  9.277 1.728 9.349 8.232 ;
     RECT  9.349 1.728 9.356 8.568 ;
     RECT  9.356 1.728 9.397 9.432 ;
     RECT  8.104 10.512 9.397 10.536 ;
     RECT  9.397 1.728 9.443 10.536 ;
     RECT  9.313 13.488 9.493 14.808 ;
     RECT  9.349 15.984 9.533 16.008 ;
     RECT  9.541 0.24 9.548 0.264 ;
     RECT  9.548 0.144 9.635 0.264 ;
     RECT  9.635 0.24 9.781 0.264 ;
     RECT  9.493 13.488 9.829 14.856 ;
     RECT  9.443 1.728 9.929 8.568 ;
     RECT  9.781 0.24 10.019 0.552 ;
     RECT  9.443 10.272 10.357 10.536 ;
     RECT  10.019 0.528 10.361 0.552 ;
     RECT  10.357 16.56 10.499 16.68 ;
     RECT  9.929 1.968 10.508 8.568 ;
     RECT  10.357 10.272 10.508 11.4 ;
     RECT  9.829 13.488 10.508 15.432 ;
     RECT  10.508 1.968 10.643 15.432 ;
     RECT  10.643 1.968 10.739 14.862 ;
     RECT  10.499 16.56 10.757 16.584 ;
     RECT  10.739 2.418 10.804 14.862 ;
    LAYER M5 ;
     RECT  9.6 0.133 9.624 0.144 ;
     RECT  2.376 0.144 2.592 0.192 ;
     RECT  2.616 0.144 2.832 0.192 ;
     RECT  2.856 0.144 3.12 0.192 ;
     RECT  3.144 0.144 3.36 0.192 ;
     RECT  3.384 0.144 3.6 0.192 ;
     RECT  3.624 0.144 3.84 0.192 ;
     RECT  3.864 0.144 4.128 0.192 ;
     RECT  4.152 0.144 4.368 0.192 ;
     RECT  4.392 0.144 4.608 0.192 ;
     RECT  4.632 0.144 4.896 0.192 ;
     RECT  4.92 0.144 5.136 0.192 ;
     RECT  5.16 0.144 5.376 0.192 ;
     RECT  5.4 0.144 5.664 0.192 ;
     RECT  5.688 0.144 5.904 0.192 ;
     RECT  5.928 0.144 6.144 0.192 ;
     RECT  6.168 0.144 6.384 0.192 ;
     RECT  6.408 0.144 6.672 0.192 ;
     RECT  6.696 0.144 6.912 0.192 ;
     RECT  6.936 0.144 7.152 0.192 ;
     RECT  7.176 0.144 7.44 0.192 ;
     RECT  7.464 0.144 7.68 0.192 ;
     RECT  7.704 0.144 7.92 0.192 ;
     RECT  7.944 0.144 8.16 0.192 ;
     RECT  8.184 0.144 8.448 0.192 ;
     RECT  8.472 0.144 8.688 0.192 ;
     RECT  8.712 0.144 8.928 0.192 ;
     RECT  8.952 0.144 9.216 0.192 ;
     RECT  9.24 0.144 9.456 0.192 ;
     RECT  9.48 0.144 9.696 0.192 ;
     RECT  9.72 0.144 9.984 0.192 ;
     RECT  10.008 0.144 10.224 0.192 ;
     RECT  10.248 0.144 10.464 0.192 ;
     RECT  10.488 0.144 10.704 0.192 ;
     RECT  2.352 0.192 10.728 1.763 ;
     RECT  3.84 1.763 10.728 1.811 ;
     RECT  2.4 1.763 2.856 1.859 ;
     RECT  4.128 1.811 10.728 2.151 ;
     RECT  2.4 1.859 2.808 3.685 ;
     RECT  4.128 2.151 10.812 3.685 ;
     RECT  2.4 3.685 10.812 4.163 ;
     RECT  3.744 4.163 10.812 4.547 ;
     RECT  4.032 4.547 10.812 5.507 ;
     RECT  4.128 5.507 10.812 5.747 ;
     RECT  4.272 5.747 10.812 6.323 ;
     RECT  4.656 6.323 10.812 7.381 ;
     RECT  2.4 4.163 2.712 7.717 ;
     RECT  2.4 7.717 3.384 7.909 ;
     RECT  4.608 7.381 10.812 7.909 ;
     RECT  2.4 7.909 10.812 13.715 ;
     RECT  2.4 13.715 6.12 14.821 ;
     RECT  7.392 13.715 10.812 14.821 ;
     RECT  2.4 14.821 10.812 15.129 ;
     RECT  2.4 15.129 10.632 15.143 ;
     RECT  2.832 15.143 10.632 16.549 ;
     RECT  2.352 16.549 10.632 17.088 ;
     RECT  2.376 17.088 2.592 17.104 ;
     RECT  2.616 17.088 2.832 17.104 ;
     RECT  2.856 17.088 3.072 17.104 ;
     RECT  3.096 17.088 3.36 17.104 ;
     RECT  3.384 17.088 3.6 17.104 ;
     RECT  3.624 17.088 3.84 17.104 ;
     RECT  3.864 17.088 4.08 17.104 ;
     RECT  4.104 17.088 4.32 17.104 ;
     RECT  4.344 17.088 4.608 17.104 ;
     RECT  4.632 17.088 4.848 17.104 ;
     RECT  4.872 17.088 5.088 17.104 ;
     RECT  5.112 17.088 5.328 17.104 ;
     RECT  5.352 17.088 5.568 17.104 ;
     RECT  5.592 17.088 5.856 17.104 ;
     RECT  5.88 17.088 6.096 17.104 ;
     RECT  6.12 17.088 6.336 17.104 ;
     RECT  6.36 17.088 6.576 17.104 ;
     RECT  6.6 17.088 6.864 17.104 ;
     RECT  6.888 17.088 7.104 17.104 ;
     RECT  7.128 17.088 7.344 17.104 ;
     RECT  7.368 17.088 7.584 17.104 ;
     RECT  7.608 17.088 7.824 17.104 ;
     RECT  7.848 17.088 8.112 17.104 ;
     RECT  8.136 17.088 8.352 17.104 ;
     RECT  8.376 17.088 8.592 17.104 ;
     RECT  8.616 17.088 8.832 17.104 ;
     RECT  8.856 17.088 9.12 17.104 ;
     RECT  9.144 17.088 9.36 17.104 ;
     RECT  9.384 17.088 9.6 17.104 ;
     RECT  9.624 17.088 9.84 17.104 ;
     RECT  9.864 17.088 10.08 17.104 ;
     RECT  10.104 17.088 10.368 17.104 ;
     RECT  10.392 17.088 10.608 17.104 ;
     RECT  2.856 1.763 3.84 1.811 ;
     RECT  2.856 1.811 4.128 1.859 ;
     RECT  2.808 1.859 4.128 3.685 ;
     RECT  2.712 4.163 3.744 4.547 ;
     RECT  2.712 4.547 4.032 5.507 ;
     RECT  2.712 5.507 4.128 5.747 ;
     RECT  4.272 6.323 4.656 7.381 ;
     RECT  4.272 7.381 4.608 7.717 ;
     RECT  3.384 7.717 4.608 7.909 ;
     RECT  6.12 13.715 7.392 14.821 ;
     RECT  2.4 15.143 2.832 16.549 ;
  END
END dsfd_dvrly_68_SN
END LIBRARY
